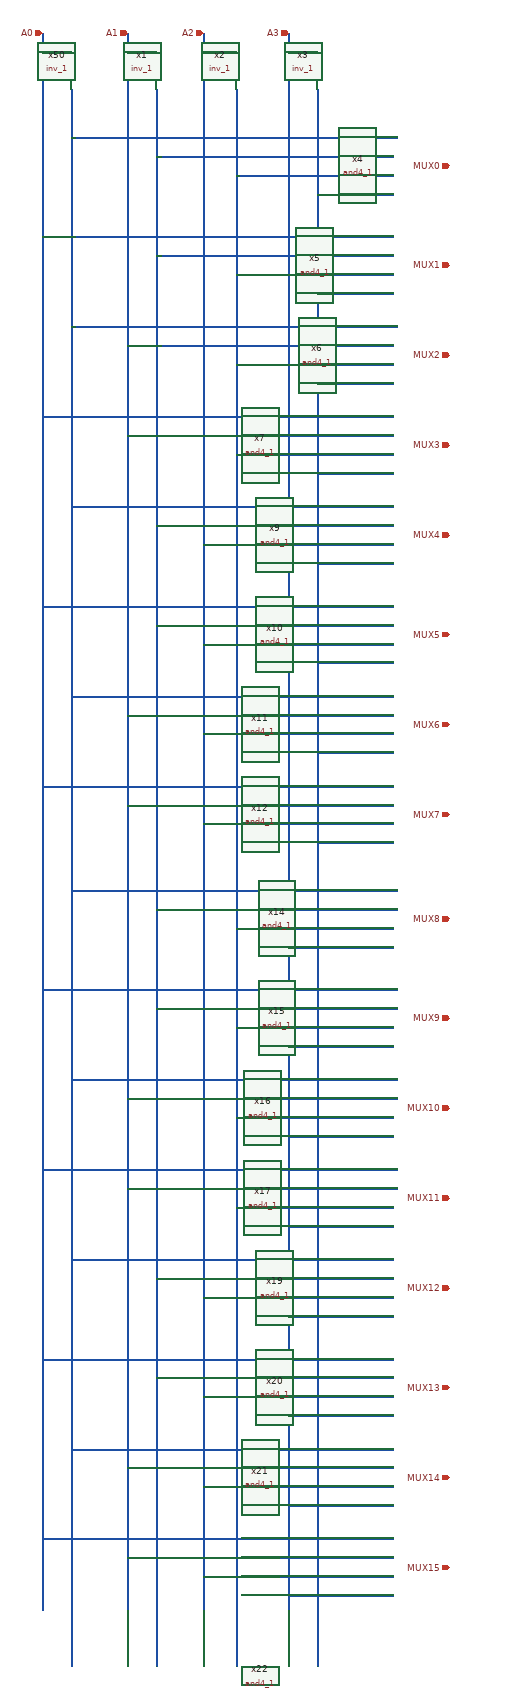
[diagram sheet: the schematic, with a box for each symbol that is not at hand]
v {xschem version=3.4.8RC file_version=1.3}
G {}
K {}
V {}
S {}
F {}
E {}
N -20 -80 40 -80 {lab=A0}
N 160 -80 220 -80 {lab=A1}
N 320 -80 390 -80 {lab=A2}
N 500 -80 560 -80 {lab=A3}
N -20 -120 -20 3210 {lab=A0}
N 160 -120 160 3210 {lab=A1}
N 320 -120 320 3210 {lab=A2}
N 500 -120 500 3210 {lab=A3}
N 40 0 40 3330 {lab=#net1}
N 220 0 220 3330 {lab=#net2}
N 390 0 390 3330 {lab=#net3}
N 560 0 560 3330 {lab=#net4}
N 40 100 730 100 {lab=#net1}
N 220 140 720 140 {lab=#net2}
N 390 180 720 180 {lab=#net3}
N 560 220 720 220 {lab=#net4}
N -20 310 720 310 {lab=A0}
N 220 350 720 350 {lab=#net2}
N 390 390 720 390 {lab=#net3}
N 560 430 720 430 {lab=#net4}
N 40 500 730 500 {lab=#net1}
N -20 690 720 690 {lab=A0}
N -20 1090 720 1090 {lab=A0}
N 40 880 720 880 {lab=#net1}
N -20 1470 720 1470 {lab=A0}
N 40 1280 720 1280 {lab=#net1}
N -10 1900 730 1900 {lab=A0}
N 50 1690 730 1690 {lab=#net1}
N 40 1690 50 1690 {lab=#net1}
N -20 1900 -10 1900 {lab=A0}
N -10 2280 730 2280 {lab=A0}
N 50 2090 730 2090 {lab=#net1}
N 40 2090 50 2090 {lab=#net1}
N -20 2280 -10 2280 {lab=A0}
N -20 2680 720 2680 {lab=A0}
N 40 2470 720 2470 {lab=#net1}
N -20 3060 720 3060 {lab=A0}
N 40 2870 720 2870 {lab=#net1}
N 160 540 720 540 {lab=A1}
N 160 730 720 730 {lab=A1}
N 220 920 720 920 {lab=#net2}
N 220 1130 720 1130 {lab=#net2}
N 160 1320 720 1320 {lab=A1}
N 160 1510 720 1510 {lab=A1}
N 230 1730 730 1730 {lab=#net2}
N 230 1940 730 1940 {lab=#net2}
N 170 2130 730 2130 {lab=A1}
N 170 2320 730 2320 {lab=A1}
N 220 1730 230 1730 {lab=#net2}
N 220 1940 230 1940 {lab=#net2}
N 160 2130 170 2130 {lab=A1}
N 160 2320 170 2320 {lab=A1}
N 220 2510 720 2510 {lab=#net2}
N 220 2720 720 2720 {lab=#net2}
N 160 2910 720 2910 {lab=A1}
N 160 3100 720 3100 {lab=A1}
N 390 580 720 580 {lab=#net3}
N 390 770 720 770 {lab=#net3}
N 320 960 720 960 {lab=A2}
N 320 1170 720 1170 {lab=A2}
N 320 1360 720 1360 {lab=A2}
N 320 1550 720 1550 {lab=A2}
N 390 1770 720 1770 {lab=#net3}
N 390 1980 720 1980 {lab=#net3}
N 390 2170 720 2170 {lab=#net3}
N 390 2360 720 2360 {lab=#net3}
N 320 2550 720 2550 {lab=A2}
N 320 2760 720 2760 {lab=A2}
N 320 2950 720 2950 {lab=A2}
N 320 3140 720 3140 {lab=A2}
N 560 620 720 620 {lab=#net4}
N 560 810 720 810 {lab=#net4}
N 560 1000 720 1000 {lab=#net4}
N 560 1210 720 1210 {lab=#net4}
N 560 1400 720 1400 {lab=#net4}
N 560 1590 720 1590 {lab=#net4}
N 500 1810 720 1810 {lab=A3}
N 500 2020 720 2020 {lab=A3}
N 500 2210 720 2210 {lab=A3}
N 500 2400 720 2400 {lab=A3}
N 500 2590 720 2590 {lab=A3}
N 500 2800 720 2800 {lab=A3}
N 500 2990 720 2990 {lab=A3}
N 500 3180 720 3180 {lab=A3}
C {sky130_stdcells/inv_1.sym} 40 -40 1 0 {name=x50 VGND=VGND VNB=VNB VPB=VPB VPWR=VPWR prefix=sky130_fd_sc_hd__ }
C {sky130_stdcells/inv_1.sym} 220 -40 1 0 {name=x1 VGND=VGND VNB=VNB VPB=VPB VPWR=VPWR prefix=sky130_fd_sc_hd__ }
C {sky130_stdcells/inv_1.sym} 390 -40 1 0 {name=x2 VGND=VGND VNB=VNB VPB=VPB VPWR=VPWR prefix=sky130_fd_sc_hd__ }
C {sky130_stdcells/inv_1.sym} 560 -40 1 0 {name=x3 VGND=VGND VNB=VNB VPB=VPB VPWR=VPWR prefix=sky130_fd_sc_hd__ }
C {sky130_stdcells/and4_1.sym} 780 160 0 0 {name=x4 VGND=VGND VNB=VNB VPB=VPB VPWR=VPWR prefix=sky130_fd_sc_hd__ }
C {sky130_stdcells/and4_1.sym} 780 370 0 0 {name=x5 VGND=VGND VNB=VNB VPB=VPB VPWR=VPWR prefix=sky130_fd_sc_hd__ }
C {sky130_stdcells/and4_1.sym} 780 560 0 0 {name=x6 VGND=VGND VNB=VNB VPB=VPB VPWR=VPWR prefix=sky130_fd_sc_hd__ }
C {sky130_stdcells/and4_1.sym} 780 750 0 0 {name=x7 VGND=VGND VNB=VNB VPB=VPB VPWR=VPWR prefix=sky130_fd_sc_hd__ }
C {sky130_stdcells/and4_1.sym} 780 940 0 0 {name=x9 VGND=VGND VNB=VNB VPB=VPB VPWR=VPWR prefix=sky130_fd_sc_hd__ }
C {sky130_stdcells/and4_1.sym} 780 1150 0 0 {name=x10 VGND=VGND VNB=VNB VPB=VPB VPWR=VPWR prefix=sky130_fd_sc_hd__ }
C {sky130_stdcells/and4_1.sym} 780 1340 0 0 {name=x11 VGND=VGND VNB=VNB VPB=VPB VPWR=VPWR prefix=sky130_fd_sc_hd__ }
C {sky130_stdcells/and4_1.sym} 780 1530 0 0 {name=x12 VGND=VGND VNB=VNB VPB=VPB VPWR=VPWR prefix=sky130_fd_sc_hd__ }
C {sky130_stdcells/and4_1.sym} 780 1750 0 0 {name=x14 VGND=VGND VNB=VNB VPB=VPB VPWR=VPWR prefix=sky130_fd_sc_hd__ }
C {sky130_stdcells/and4_1.sym} 780 1960 0 0 {name=x15 VGND=VGND VNB=VNB VPB=VPB VPWR=VPWR prefix=sky130_fd_sc_hd__ }
C {sky130_stdcells/and4_1.sym} 780 2150 0 0 {name=x16 VGND=VGND VNB=VNB VPB=VPB VPWR=VPWR prefix=sky130_fd_sc_hd__ }
C {sky130_stdcells/and4_1.sym} 780 2340 0 0 {name=x17 VGND=VGND VNB=VNB VPB=VPB VPWR=VPWR prefix=sky130_fd_sc_hd__ }
C {sky130_stdcells/and4_1.sym} 780 2530 0 0 {name=x19 VGND=VGND VNB=VNB VPB=VPB VPWR=VPWR prefix=sky130_fd_sc_hd__ }
C {sky130_stdcells/and4_1.sym} 780 2740 0 0 {name=x20 VGND=VGND VNB=VNB VPB=VPB VPWR=VPWR prefix=sky130_fd_sc_hd__ }
C {sky130_stdcells/and4_1.sym} 780 2930 0 0 {name=x21 VGND=VGND VNB=VNB VPB=VPB VPWR=VPWR prefix=sky130_fd_sc_hd__ }
C {sky130_stdcells/and4_1.sym} 780 3120 0 0 {name=x22 VGND=VGND VNB=VNB VPB=VPB VPWR=VPWR prefix=sky130_fd_sc_hd__ }
C {iopin.sym} 840 160 0 0 {name=p4 lab=MUX0}
C {iopin.sym} 840 370 0 0 {name=p5 lab=MUX1}
C {iopin.sym} 840 560 0 0 {name=p7 lab=MUX2}
C {iopin.sym} 840 750 0 0 {name=p8 lab=MUX3}
C {iopin.sym} 840 940 0 0 {name=p9 lab=MUX4}
C {iopin.sym} 840 1150 0 0 {name=p10 lab=MUX5}
C {iopin.sym} 840 1340 0 0 {name=p11 lab=MUX6}
C {iopin.sym} 840 1530 0 0 {name=p12 lab=MUX7}
C {iopin.sym} 840 1750 0 0 {name=p13 lab=MUX8}
C {iopin.sym} 840 1960 0 0 {name=p14 lab=MUX9}
C {iopin.sym} 840 2150 0 0 {name=p15 lab=MUX10}
C {iopin.sym} 840 2340 0 0 {name=p16 lab=MUX11}
C {iopin.sym} 840 2530 0 0 {name=p17 lab=MUX12}
C {iopin.sym} 840 2740 0 0 {name=p18 lab=MUX13}
C {iopin.sym} 840 2930 0 0 {name=p19 lab=MUX14}
C {iopin.sym} 840 3120 0 0 {name=p20 lab=MUX15}
C {ipin.sym} -20 -120 1 0 {name=p21 lab=A0}
C {ipin.sym} 160 -120 1 0 {name=p1 lab=A1}
C {ipin.sym} 320 -120 1 0 {name=p2 lab=A2}
C {ipin.sym} 500 -120 1 0 {name=p3 lab=A3}
